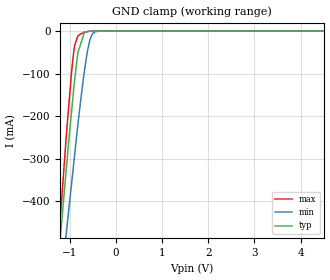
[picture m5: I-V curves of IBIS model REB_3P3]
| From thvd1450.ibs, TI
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|   REB_3P3 Model
[Model]   REB_3P3
Model_type   Input
Vinl = 0.462
Vinh = 2.211
|   typ   min   max
C_comp   6.755pF   6.133pF   7.203pF
|  Where Nom  PVT is Nominal Process,   3.3V,  25C
|   Fast PVT is Strong Process,   3.6V, -40C
|   Slow PVT is Weak Process,   3V, 150C
[Model spec]
|subparameter
Vinl   0.462   0.420   0.504
Vinh   2.211   2.010   2.412
[Voltage Range]   3.3   3   3.6
|Junction Temperature
[Temperature Range]   25   150   -40
[Power Clamp Reference]   3.3   3   3.6
[GND Clamp Reference]   0   0   0
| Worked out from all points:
|   GND clamp passes 1 mA (typ) near -0.61 V on its own axis
[GND Clamp]
|   Voltage   I(typ)   I(min)   I(max)
-3.3V     -3.279A    -2.937A    -3.78A
-1.238V   -530.8mA   -650mA     -491.1mA
-1.189V   -467.9mA   -597.2mA   -418.8mA
-1.068V   -317.9mA   -470mA     -239.5mA
-923.9mV  -148.8mA   -322.9mA   -58.91mA
-892.6mV  -115.8mA   -291mA     -34.2mA
-825mV    -51.97mA   -222mA     -11.94mA
-687.7mV  -4.558mA   -99.67mA   -2.912mA
-611.3mV  -1.108mA   -45.22mA   -946.5uA
-556.1mV  -574.6uA   -19.04mA   -375.2uA
-387.6mV  -400.9uA   -384.1uA   -8.905uA
6.6V      0A         0A         0A
[POWER Clamp]
|   Voltage   I(typ)   I(min)   I(max)
-3.3V     0A         0A         0A
0V        0A         0A         0A
6.6V      0A         0A         0A
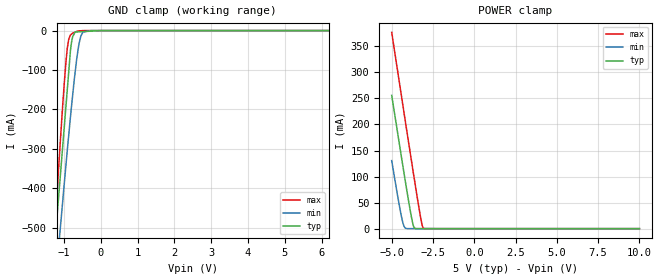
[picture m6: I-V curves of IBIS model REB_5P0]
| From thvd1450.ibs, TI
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|   REB_5P0 Model
[Model]   REB_5P0
Model_type   Input
Vinl = 0.7
Vinh = 3.35
|   typ   min   max
C_comp   6.481pF   5.776pF   6.944pF
|  Where Nom  PVT is Nominal Process,   3.3V,  25C
|   Fast PVT is Strong Process,   3.6V, -40C
|   Slow PVT is Weak Process,   3V, 150C
[Model spec]
|subparameter
Vinl   0.462   0.420   0.504
Vinh   2.211   2.010   2.412
[Voltage Range]   5   4.5   5.5
|Junction Temperature
[Temperature Range]   25   150   -40
[Power Clamp Reference]   5   4.5   5.5
[GND Clamp Reference]   0   0   0
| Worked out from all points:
|   GND clamp passes 1 mA (typ) near -0.19 V on its own axis
|   POWER clamp passes 1 mA (typ) near -3.61 V on its own axis
[GND Clamp]
|   Voltage   I(typ)   I(min)   I(max)
-5V       -5.58A     -4.856A    -6.529A
-1.25V    -545.1mA   -660.9mA   -509.1mA
-1.141V   -419.6mA   -547.1mA   -345.6mA
-1.056V   -321.5mA   -458.1mA   -222.8mA
-991.2mV  -246.4mA   -390.1mA   -135.2mA
-905.1mV  -146.8mA   -301.2mA   -42.95mA
-819.4mV  -47.67mA   -216.9mA   -11.22mA
-790.4mV  -28.63mA   -189.9mA   -8.686mA
-641.9mV  -3.437mA   -65.46mA   -1.525mA
-538.9mV  -2.886mA   -13.66mA   -443.9uA
-272.5mV  -1.46mA    -25.62uA   -5.468uA
10V       0A         0A         0A
[POWER Clamp]
|   Voltage   I(typ)   I(min)   I(max)
-5V       255.9mA    130.7mA    376.8mA
-4.542V   164mA      45.29mA    282.2mA
-4.308V   117.2mA    9.51mA     233.8mA
-4.201V   96.23mA    1.775mA    211.7mA
-4.133V   83.01mA    409.3uA    197.7mA
-3.866V   32.67mA    21.34uA    142.9mA
-3.709V   8.06mA     20.06uA    111.2mA
-3.602V   667.1uA    19.18uA    89.53mA
-3.272V   29.06uA    16.5uA     25.67mA
-3.159V   27.43uA    15.57uA    7.336mA
-3.083V   26.34uA    14.96uA    957.3uA
10V       0A         0A         0A
